VERSION 5.8 ;
BUSBITCHARS "[]" ;
DIVIDERCHAR "/" ;
UNITS
    DATABASE MICRONS 1000 ;
END UNITS

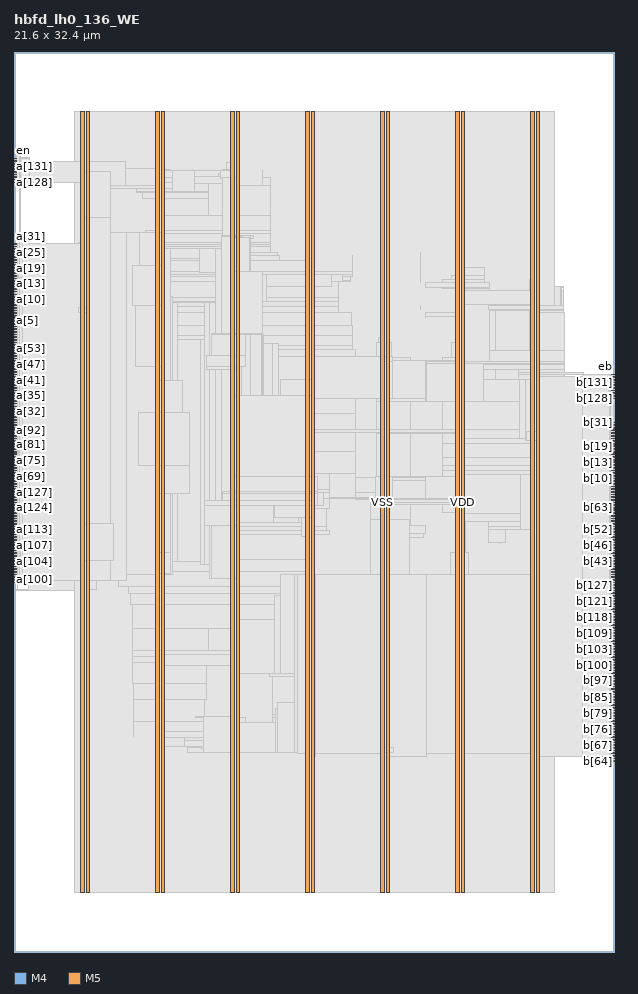
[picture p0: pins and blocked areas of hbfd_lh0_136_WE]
MACRO hbfd_lh0_136_WE
  FOREIGN hbfd_lh0_136_WE 0 0 ;
  CLASS BLOCK ;
  SIZE 21.6 BY 32.4 ;
  PIN a[0]
    DIRECTION INPUT ;
    USE SIGNAL ;
    PORT
      LAYER M4 ;
        RECT  0 22.512 0.084 22.536 ;
    END
  END a[0]
  PIN a[100]
    DIRECTION INPUT ;
    USE SIGNAL ;
    PORT
      LAYER M4 ;
        RECT  0 13.68 0.084 13.704 ;
    END
  END a[100]
  PIN a[101]
    DIRECTION INPUT ;
    USE SIGNAL ;
    PORT
      LAYER M4 ;
        RECT  0 13.776 0.084 13.8 ;
    END
  END a[101]
  PIN a[102]
    DIRECTION INPUT ;
    USE SIGNAL ;
    PORT
      LAYER M4 ;
        RECT  0 13.872 0.084 13.896 ;
    END
  END a[102]
  PIN a[103]
    DIRECTION INPUT ;
    USE SIGNAL ;
    PORT
      LAYER M4 ;
        RECT  0 13.968 0.084 13.992 ;
    END
  END a[103]
  PIN a[104]
    DIRECTION INPUT ;
    USE SIGNAL ;
    PORT
      LAYER M4 ;
        RECT  0 14.064 0.084 14.088 ;
    END
  END a[104]
  PIN a[105]
    DIRECTION INPUT ;
    USE SIGNAL ;
    PORT
      LAYER M4 ;
        RECT  0 14.16 0.084 14.184 ;
    END
  END a[105]
  PIN a[106]
    DIRECTION INPUT ;
    USE SIGNAL ;
    PORT
      LAYER M4 ;
        RECT  0 14.256 0.084 14.28 ;
    END
  END a[106]
  PIN a[107]
    DIRECTION INPUT ;
    USE SIGNAL ;
    PORT
      LAYER M4 ;
        RECT  0 14.352 0.084 14.376 ;
    END
  END a[107]
  PIN a[108]
    DIRECTION INPUT ;
    USE SIGNAL ;
    PORT
      LAYER M4 ;
        RECT  0 14.448 0.084 14.472 ;
    END
  END a[108]
  PIN a[109]
    DIRECTION INPUT ;
    USE SIGNAL ;
    PORT
      LAYER M4 ;
        RECT  0 14.544 0.084 14.568 ;
    END
  END a[109]
  PIN a[10]
    DIRECTION INPUT ;
    USE SIGNAL ;
    PORT
      LAYER M4 ;
        RECT  0 23.472 0.084 23.496 ;
    END
  END a[10]
  PIN a[110]
    DIRECTION INPUT ;
    USE SIGNAL ;
    PORT
      LAYER M4 ;
        RECT  0 14.64 0.084 14.664 ;
    END
  END a[110]
  PIN a[111]
    DIRECTION INPUT ;
    USE SIGNAL ;
    PORT
      LAYER M4 ;
        RECT  0 14.736 0.084 14.76 ;
    END
  END a[111]
  PIN a[112]
    DIRECTION INPUT ;
    USE SIGNAL ;
    PORT
      LAYER M4 ;
        RECT  0 14.832 0.084 14.856 ;
    END
  END a[112]
  PIN a[113]
    DIRECTION INPUT ;
    USE SIGNAL ;
    PORT
      LAYER M4 ;
        RECT  0 14.928 0.084 14.952 ;
    END
  END a[113]
  PIN a[114]
    DIRECTION INPUT ;
    USE SIGNAL ;
    PORT
      LAYER M4 ;
        RECT  0 15.024 0.084 15.048 ;
    END
  END a[114]
  PIN a[115]
    DIRECTION INPUT ;
    USE SIGNAL ;
    PORT
      LAYER M4 ;
        RECT  0 15.12 0.084 15.144 ;
    END
  END a[115]
  PIN a[116]
    DIRECTION INPUT ;
    USE SIGNAL ;
    PORT
      LAYER M4 ;
        RECT  0 15.216 0.084 15.24 ;
    END
  END a[116]
  PIN a[117]
    DIRECTION INPUT ;
    USE SIGNAL ;
    PORT
      LAYER M4 ;
        RECT  0 15.312 0.084 15.336 ;
    END
  END a[117]
  PIN a[118]
    DIRECTION INPUT ;
    USE SIGNAL ;
    PORT
      LAYER M4 ;
        RECT  0 15.408 0.084 15.432 ;
    END
  END a[118]
  PIN a[119]
    DIRECTION INPUT ;
    USE SIGNAL ;
    PORT
      LAYER M4 ;
        RECT  0 15.504 0.084 15.528 ;
    END
  END a[119]
  PIN a[11]
    DIRECTION INPUT ;
    USE SIGNAL ;
    PORT
      LAYER M4 ;
        RECT  0 23.568 0.084 23.592 ;
    END
  END a[11]
  PIN a[120]
    DIRECTION INPUT ;
    USE SIGNAL ;
    PORT
      LAYER M4 ;
        RECT  0 15.6 0.084 15.624 ;
    END
  END a[120]
  PIN a[121]
    DIRECTION INPUT ;
    USE SIGNAL ;
    PORT
      LAYER M4 ;
        RECT  0 15.696 0.084 15.72 ;
    END
  END a[121]
  PIN a[122]
    DIRECTION INPUT ;
    USE SIGNAL ;
    PORT
      LAYER M4 ;
        RECT  0 15.792 0.084 15.816 ;
    END
  END a[122]
  PIN a[123]
    DIRECTION INPUT ;
    USE SIGNAL ;
    PORT
      LAYER M4 ;
        RECT  0 15.888 0.084 15.912 ;
    END
  END a[123]
  PIN a[124]
    DIRECTION INPUT ;
    USE SIGNAL ;
    PORT
      LAYER M4 ;
        RECT  0 15.984 0.084 16.008 ;
    END
  END a[124]
  PIN a[125]
    DIRECTION INPUT ;
    USE SIGNAL ;
    PORT
      LAYER M4 ;
        RECT  0 16.08 0.084 16.104 ;
    END
  END a[125]
  PIN a[126]
    DIRECTION INPUT ;
    USE SIGNAL ;
    PORT
      LAYER M4 ;
        RECT  0 16.176 0.084 16.2 ;
    END
  END a[126]
  PIN a[127]
    DIRECTION INPUT ;
    USE SIGNAL ;
    PORT
      LAYER M4 ;
        RECT  0 16.272 0.084 16.296 ;
    END
  END a[127]
  PIN a[128]
    DIRECTION INPUT ;
    USE SIGNAL ;
    PORT
      LAYER M4 ;
        RECT  0 27.696 0.084 27.72 ;
    END
  END a[128]
  PIN a[129]
    DIRECTION INPUT ;
    USE SIGNAL ;
    PORT
      LAYER M4 ;
        RECT  0 27.792 0.084 27.816 ;
    END
  END a[129]
  PIN a[12]
    DIRECTION INPUT ;
    USE SIGNAL ;
    PORT
      LAYER M4 ;
        RECT  0 23.664 0.084 23.688 ;
    END
  END a[12]
  PIN a[130]
    DIRECTION INPUT ;
    USE SIGNAL ;
    PORT
      LAYER M4 ;
        RECT  0 27.888 0.084 27.912 ;
    END
  END a[130]
  PIN a[131]
    DIRECTION INPUT ;
    USE SIGNAL ;
    PORT
      LAYER M4 ;
        RECT  0 27.984 0.084 28.008 ;
    END
  END a[131]
  PIN a[132]
    DIRECTION INPUT ;
    USE SIGNAL ;
    PORT
      LAYER M4 ;
        RECT  0 28.08 0.084 28.104 ;
    END
  END a[132]
  PIN a[133]
    DIRECTION INPUT ;
    USE SIGNAL ;
    PORT
      LAYER M4 ;
        RECT  0 28.176 0.084 28.2 ;
    END
  END a[133]
  PIN a[134]
    DIRECTION INPUT ;
    USE SIGNAL ;
    PORT
      LAYER M4 ;
        RECT  0 28.272 0.084 28.296 ;
    END
  END a[134]
  PIN a[135]
    DIRECTION INPUT ;
    USE SIGNAL ;
    PORT
      LAYER M4 ;
        RECT  0 28.368 0.084 28.392 ;
    END
  END a[135]
  PIN a[13]
    DIRECTION INPUT ;
    USE SIGNAL ;
    PORT
      LAYER M4 ;
        RECT  0 23.76 0.084 23.784 ;
    END
  END a[13]
  PIN a[14]
    DIRECTION INPUT ;
    USE SIGNAL ;
    PORT
      LAYER M4 ;
        RECT  0 23.856 0.084 23.88 ;
    END
  END a[14]
  PIN a[15]
    DIRECTION INPUT ;
    USE SIGNAL ;
    PORT
      LAYER M4 ;
        RECT  0 23.952 0.084 23.976 ;
    END
  END a[15]
  PIN a[16]
    DIRECTION INPUT ;
    USE SIGNAL ;
    PORT
      LAYER M4 ;
        RECT  0 24.048 0.084 24.072 ;
    END
  END a[16]
  PIN a[17]
    DIRECTION INPUT ;
    USE SIGNAL ;
    PORT
      LAYER M4 ;
        RECT  0 24.144 0.084 24.168 ;
    END
  END a[17]
  PIN a[18]
    DIRECTION INPUT ;
    USE SIGNAL ;
    PORT
      LAYER M4 ;
        RECT  0 24.24 0.084 24.264 ;
    END
  END a[18]
  PIN a[19]
    DIRECTION INPUT ;
    USE SIGNAL ;
    PORT
      LAYER M4 ;
        RECT  0 24.336 0.084 24.36 ;
    END
  END a[19]
  PIN a[1]
    DIRECTION INPUT ;
    USE SIGNAL ;
    PORT
      LAYER M4 ;
        RECT  0 22.608 0.084 22.632 ;
    END
  END a[1]
  PIN a[20]
    DIRECTION INPUT ;
    USE SIGNAL ;
    PORT
      LAYER M4 ;
        RECT  0 24.432 0.084 24.456 ;
    END
  END a[20]
  PIN a[21]
    DIRECTION INPUT ;
    USE SIGNAL ;
    PORT
      LAYER M4 ;
        RECT  0 24.528 0.084 24.552 ;
    END
  END a[21]
  PIN a[22]
    DIRECTION INPUT ;
    USE SIGNAL ;
    PORT
      LAYER M4 ;
        RECT  0 24.624 0.084 24.648 ;
    END
  END a[22]
  PIN a[23]
    DIRECTION INPUT ;
    USE SIGNAL ;
    PORT
      LAYER M4 ;
        RECT  0 24.72 0.084 24.744 ;
    END
  END a[23]
  PIN a[24]
    DIRECTION INPUT ;
    USE SIGNAL ;
    PORT
      LAYER M4 ;
        RECT  0 24.816 0.084 24.84 ;
    END
  END a[24]
  PIN a[25]
    DIRECTION INPUT ;
    USE SIGNAL ;
    PORT
      LAYER M4 ;
        RECT  0 24.912 0.084 24.936 ;
    END
  END a[25]
  PIN a[26]
    DIRECTION INPUT ;
    USE SIGNAL ;
    PORT
      LAYER M4 ;
        RECT  0 25.008 0.084 25.032 ;
    END
  END a[26]
  PIN a[27]
    DIRECTION INPUT ;
    USE SIGNAL ;
    PORT
      LAYER M4 ;
        RECT  0 25.104 0.084 25.128 ;
    END
  END a[27]
  PIN a[28]
    DIRECTION INPUT ;
    USE SIGNAL ;
    PORT
      LAYER M4 ;
        RECT  0 25.2 0.084 25.224 ;
    END
  END a[28]
  PIN a[29]
    DIRECTION INPUT ;
    USE SIGNAL ;
    PORT
      LAYER M4 ;
        RECT  0 25.296 0.084 25.32 ;
    END
  END a[29]
  PIN a[2]
    DIRECTION INPUT ;
    USE SIGNAL ;
    PORT
      LAYER M4 ;
        RECT  0 22.704 0.084 22.728 ;
    END
  END a[2]
  PIN a[30]
    DIRECTION INPUT ;
    USE SIGNAL ;
    PORT
      LAYER M4 ;
        RECT  0 25.392 0.084 25.416 ;
    END
  END a[30]
  PIN a[31]
    DIRECTION INPUT ;
    USE SIGNAL ;
    PORT
      LAYER M4 ;
        RECT  0 25.488 0.084 25.512 ;
    END
  END a[31]
  PIN a[32]
    DIRECTION INPUT ;
    USE SIGNAL ;
    PORT
      LAYER M4 ;
        RECT  0 19.44 0.084 19.464 ;
    END
  END a[32]
  PIN a[33]
    DIRECTION INPUT ;
    USE SIGNAL ;
    PORT
      LAYER M4 ;
        RECT  0 19.536 0.084 19.56 ;
    END
  END a[33]
  PIN a[34]
    DIRECTION INPUT ;
    USE SIGNAL ;
    PORT
      LAYER M4 ;
        RECT  0 19.632 0.084 19.656 ;
    END
  END a[34]
  PIN a[35]
    DIRECTION INPUT ;
    USE SIGNAL ;
    PORT
      LAYER M4 ;
        RECT  0 19.728 0.084 19.752 ;
    END
  END a[35]
  PIN a[36]
    DIRECTION INPUT ;
    USE SIGNAL ;
    PORT
      LAYER M4 ;
        RECT  0 19.824 0.084 19.848 ;
    END
  END a[36]
  PIN a[37]
    DIRECTION INPUT ;
    USE SIGNAL ;
    PORT
      LAYER M4 ;
        RECT  0 19.92 0.084 19.944 ;
    END
  END a[37]
  PIN a[38]
    DIRECTION INPUT ;
    USE SIGNAL ;
    PORT
      LAYER M4 ;
        RECT  0 20.016 0.084 20.04 ;
    END
  END a[38]
  PIN a[39]
    DIRECTION INPUT ;
    USE SIGNAL ;
    PORT
      LAYER M4 ;
        RECT  0 20.112 0.084 20.136 ;
    END
  END a[39]
  PIN a[3]
    DIRECTION INPUT ;
    USE SIGNAL ;
    PORT
      LAYER M4 ;
        RECT  0 22.8 0.084 22.824 ;
    END
  END a[3]
  PIN a[40]
    DIRECTION INPUT ;
    USE SIGNAL ;
    PORT
      LAYER M4 ;
        RECT  0 20.208 0.084 20.232 ;
    END
  END a[40]
  PIN a[41]
    DIRECTION INPUT ;
    USE SIGNAL ;
    PORT
      LAYER M4 ;
        RECT  0 20.304 0.084 20.328 ;
    END
  END a[41]
  PIN a[42]
    DIRECTION INPUT ;
    USE SIGNAL ;
    PORT
      LAYER M4 ;
        RECT  0 20.4 0.084 20.424 ;
    END
  END a[42]
  PIN a[43]
    DIRECTION INPUT ;
    USE SIGNAL ;
    PORT
      LAYER M4 ;
        RECT  0 20.496 0.084 20.52 ;
    END
  END a[43]
  PIN a[44]
    DIRECTION INPUT ;
    USE SIGNAL ;
    PORT
      LAYER M4 ;
        RECT  0 20.592 0.084 20.616 ;
    END
  END a[44]
  PIN a[45]
    DIRECTION INPUT ;
    USE SIGNAL ;
    PORT
      LAYER M4 ;
        RECT  0 20.688 0.084 20.712 ;
    END
  END a[45]
  PIN a[46]
    DIRECTION INPUT ;
    USE SIGNAL ;
    PORT
      LAYER M4 ;
        RECT  0 20.784 0.084 20.808 ;
    END
  END a[46]
  PIN a[47]
    DIRECTION INPUT ;
    USE SIGNAL ;
    PORT
      LAYER M4 ;
        RECT  0 20.88 0.084 20.904 ;
    END
  END a[47]
  PIN a[48]
    DIRECTION INPUT ;
    USE SIGNAL ;
    PORT
      LAYER M4 ;
        RECT  0 20.976 0.084 21 ;
    END
  END a[48]
  PIN a[49]
    DIRECTION INPUT ;
    USE SIGNAL ;
    PORT
      LAYER M4 ;
        RECT  0 21.072 0.084 21.096 ;
    END
  END a[49]
  PIN a[4]
    DIRECTION INPUT ;
    USE SIGNAL ;
    PORT
      LAYER M4 ;
        RECT  0 22.896 0.084 22.92 ;
    END
  END a[4]
  PIN a[50]
    DIRECTION INPUT ;
    USE SIGNAL ;
    PORT
      LAYER M4 ;
        RECT  0 21.168 0.084 21.192 ;
    END
  END a[50]
  PIN a[51]
    DIRECTION INPUT ;
    USE SIGNAL ;
    PORT
      LAYER M4 ;
        RECT  0 21.264 0.084 21.288 ;
    END
  END a[51]
  PIN a[52]
    DIRECTION INPUT ;
    USE SIGNAL ;
    PORT
      LAYER M4 ;
        RECT  0 21.36 0.084 21.384 ;
    END
  END a[52]
  PIN a[53]
    DIRECTION INPUT ;
    USE SIGNAL ;
    PORT
      LAYER M4 ;
        RECT  0 21.456 0.084 21.48 ;
    END
  END a[53]
  PIN a[54]
    DIRECTION INPUT ;
    USE SIGNAL ;
    PORT
      LAYER M4 ;
        RECT  0 21.552 0.084 21.576 ;
    END
  END a[54]
  PIN a[55]
    DIRECTION INPUT ;
    USE SIGNAL ;
    PORT
      LAYER M4 ;
        RECT  0 21.648 0.084 21.672 ;
    END
  END a[55]
  PIN a[56]
    DIRECTION INPUT ;
    USE SIGNAL ;
    PORT
      LAYER M4 ;
        RECT  0 21.744 0.084 21.768 ;
    END
  END a[56]
  PIN a[57]
    DIRECTION INPUT ;
    USE SIGNAL ;
    PORT
      LAYER M4 ;
        RECT  0 21.84 0.084 21.864 ;
    END
  END a[57]
  PIN a[58]
    DIRECTION INPUT ;
    USE SIGNAL ;
    PORT
      LAYER M4 ;
        RECT  0 21.936 0.084 21.96 ;
    END
  END a[58]
  PIN a[59]
    DIRECTION INPUT ;
    USE SIGNAL ;
    PORT
      LAYER M4 ;
        RECT  0 22.032 0.084 22.056 ;
    END
  END a[59]
  PIN a[5]
    DIRECTION INPUT ;
    USE SIGNAL ;
    PORT
      LAYER M4 ;
        RECT  0 22.992 0.084 23.016 ;
    END
  END a[5]
  PIN a[60]
    DIRECTION INPUT ;
    USE SIGNAL ;
    PORT
      LAYER M4 ;
        RECT  0 22.128 0.084 22.152 ;
    END
  END a[60]
  PIN a[61]
    DIRECTION INPUT ;
    USE SIGNAL ;
    PORT
      LAYER M4 ;
        RECT  0 22.224 0.084 22.248 ;
    END
  END a[61]
  PIN a[62]
    DIRECTION INPUT ;
    USE SIGNAL ;
    PORT
      LAYER M4 ;
        RECT  0 22.32 0.084 22.344 ;
    END
  END a[62]
  PIN a[63]
    DIRECTION INPUT ;
    USE SIGNAL ;
    PORT
      LAYER M4 ;
        RECT  0 22.416 0.084 22.44 ;
    END
  END a[63]
  PIN a[64]
    DIRECTION INPUT ;
    USE SIGNAL ;
    PORT
      LAYER M4 ;
        RECT  0 16.368 0.084 16.392 ;
    END
  END a[64]
  PIN a[65]
    DIRECTION INPUT ;
    USE SIGNAL ;
    PORT
      LAYER M4 ;
        RECT  0 16.464 0.084 16.488 ;
    END
  END a[65]
  PIN a[66]
    DIRECTION INPUT ;
    USE SIGNAL ;
    PORT
      LAYER M4 ;
        RECT  0 16.56 0.084 16.584 ;
    END
  END a[66]
  PIN a[67]
    DIRECTION INPUT ;
    USE SIGNAL ;
    PORT
      LAYER M4 ;
        RECT  0 16.656 0.084 16.68 ;
    END
  END a[67]
  PIN a[68]
    DIRECTION INPUT ;
    USE SIGNAL ;
    PORT
      LAYER M4 ;
        RECT  0 16.752 0.084 16.776 ;
    END
  END a[68]
  PIN a[69]
    DIRECTION INPUT ;
    USE SIGNAL ;
    PORT
      LAYER M4 ;
        RECT  0 16.848 0.084 16.872 ;
    END
  END a[69]
  PIN a[6]
    DIRECTION INPUT ;
    USE SIGNAL ;
    PORT
      LAYER M4 ;
        RECT  0 23.088 0.084 23.112 ;
    END
  END a[6]
  PIN a[70]
    DIRECTION INPUT ;
    USE SIGNAL ;
    PORT
      LAYER M4 ;
        RECT  0 16.944 0.084 16.968 ;
    END
  END a[70]
  PIN a[71]
    DIRECTION INPUT ;
    USE SIGNAL ;
    PORT
      LAYER M4 ;
        RECT  0 17.04 0.084 17.064 ;
    END
  END a[71]
  PIN a[72]
    DIRECTION INPUT ;
    USE SIGNAL ;
    PORT
      LAYER M4 ;
        RECT  0 17.136 0.084 17.16 ;
    END
  END a[72]
  PIN a[73]
    DIRECTION INPUT ;
    USE SIGNAL ;
    PORT
      LAYER M4 ;
        RECT  0 17.232 0.084 17.256 ;
    END
  END a[73]
  PIN a[74]
    DIRECTION INPUT ;
    USE SIGNAL ;
    PORT
      LAYER M4 ;
        RECT  0 17.328 0.084 17.352 ;
    END
  END a[74]
  PIN a[75]
    DIRECTION INPUT ;
    USE SIGNAL ;
    PORT
      LAYER M4 ;
        RECT  0 17.424 0.084 17.448 ;
    END
  END a[75]
  PIN a[76]
    DIRECTION INPUT ;
    USE SIGNAL ;
    PORT
      LAYER M4 ;
        RECT  0 17.52 0.084 17.544 ;
    END
  END a[76]
  PIN a[77]
    DIRECTION INPUT ;
    USE SIGNAL ;
    PORT
      LAYER M4 ;
        RECT  0 17.616 0.084 17.64 ;
    END
  END a[77]
  PIN a[78]
    DIRECTION INPUT ;
    USE SIGNAL ;
    PORT
      LAYER M4 ;
        RECT  0 17.712 0.084 17.736 ;
    END
  END a[78]
  PIN a[79]
    DIRECTION INPUT ;
    USE SIGNAL ;
    PORT
      LAYER M4 ;
        RECT  0 17.808 0.084 17.832 ;
    END
  END a[79]
  PIN a[7]
    DIRECTION INPUT ;
    USE SIGNAL ;
    PORT
      LAYER M4 ;
        RECT  0 23.184 0.084 23.208 ;
    END
  END a[7]
  PIN a[80]
    DIRECTION INPUT ;
    USE SIGNAL ;
    PORT
      LAYER M4 ;
        RECT  0 17.904 0.084 17.928 ;
    END
  END a[80]
  PIN a[81]
    DIRECTION INPUT ;
    USE SIGNAL ;
    PORT
      LAYER M4 ;
        RECT  0 18 0.084 18.024 ;
    END
  END a[81]
  PIN a[82]
    DIRECTION INPUT ;
    USE SIGNAL ;
    PORT
      LAYER M4 ;
        RECT  0 18.096 0.084 18.12 ;
    END
  END a[82]
  PIN a[83]
    DIRECTION INPUT ;
    USE SIGNAL ;
    PORT
      LAYER M4 ;
        RECT  0 18.192 0.084 18.216 ;
    END
  END a[83]
  PIN a[84]
    DIRECTION INPUT ;
    USE SIGNAL ;
    PORT
      LAYER M4 ;
        RECT  0 18.288 0.084 18.312 ;
    END
  END a[84]
  PIN a[85]
    DIRECTION INPUT ;
    USE SIGNAL ;
    PORT
      LAYER M4 ;
        RECT  0 18.384 0.084 18.408 ;
    END
  END a[85]
  PIN a[86]
    DIRECTION INPUT ;
    USE SIGNAL ;
    PORT
      LAYER M4 ;
        RECT  0 18.48 0.084 18.504 ;
    END
  END a[86]
  PIN a[87]
    DIRECTION INPUT ;
    USE SIGNAL ;
    PORT
      LAYER M4 ;
        RECT  0 18.576 0.084 18.6 ;
    END
  END a[87]
  PIN a[88]
    DIRECTION INPUT ;
    USE SIGNAL ;
    PORT
      LAYER M4 ;
        RECT  0 18.672 0.084 18.696 ;
    END
  END a[88]
  PIN a[89]
    DIRECTION INPUT ;
    USE SIGNAL ;
    PORT
      LAYER M4 ;
        RECT  0 18.768 0.084 18.792 ;
    END
  END a[89]
  PIN a[8]
    DIRECTION INPUT ;
    USE SIGNAL ;
    PORT
      LAYER M4 ;
        RECT  0 23.28 0.084 23.304 ;
    END
  END a[8]
  PIN a[90]
    DIRECTION INPUT ;
    USE SIGNAL ;
    PORT
      LAYER M4 ;
        RECT  0 18.864 0.084 18.888 ;
    END
  END a[90]
  PIN a[91]
    DIRECTION INPUT ;
    USE SIGNAL ;
    PORT
      LAYER M4 ;
        RECT  0 18.96 0.084 18.984 ;
    END
  END a[91]
  PIN a[92]
    DIRECTION INPUT ;
    USE SIGNAL ;
    PORT
      LAYER M4 ;
        RECT  0 19.056 0.084 19.08 ;
    END
  END a[92]
  PIN a[93]
    DIRECTION INPUT ;
    USE SIGNAL ;
    PORT
      LAYER M4 ;
        RECT  0 19.152 0.084 19.176 ;
    END
  END a[93]
  PIN a[94]
    DIRECTION INPUT ;
    USE SIGNAL ;
    PORT
      LAYER M4 ;
        RECT  0 19.248 0.084 19.272 ;
    END
  END a[94]
  PIN a[95]
    DIRECTION INPUT ;
    USE SIGNAL ;
    PORT
      LAYER M4 ;
        RECT  0 19.344 0.084 19.368 ;
    END
  END a[95]
  PIN a[96]
    DIRECTION INPUT ;
    USE SIGNAL ;
    PORT
      LAYER M4 ;
        RECT  0 13.296 0.084 13.32 ;
    END
  END a[96]
  PIN a[97]
    DIRECTION INPUT ;
    USE SIGNAL ;
    PORT
      LAYER M4 ;
        RECT  0 13.392 0.084 13.416 ;
    END
  END a[97]
  PIN a[98]
    DIRECTION INPUT ;
    USE SIGNAL ;
    PORT
      LAYER M4 ;
        RECT  0 13.488 0.084 13.512 ;
    END
  END a[98]
  PIN a[99]
    DIRECTION INPUT ;
    USE SIGNAL ;
    PORT
      LAYER M4 ;
        RECT  0 13.584 0.084 13.608 ;
    END
  END a[99]
  PIN a[9]
    DIRECTION INPUT ;
    USE SIGNAL ;
    PORT
      LAYER M4 ;
        RECT  0 23.376 0.084 23.4 ;
    END
  END a[9]
  PIN b[0]
    DIRECTION OUTPUT ;
    USE SIGNAL ;
    PORT
      LAYER M4 ;
        RECT  21.516 16.08 21.6 16.104 ;
    END
  END b[0]
  PIN b[100]
    DIRECTION OUTPUT ;
    USE SIGNAL ;
    PORT
      LAYER M4 ;
        RECT  21.516 10.32 21.6 10.344 ;
    END
  END b[100]
  PIN b[101]
    DIRECTION OUTPUT ;
    USE SIGNAL ;
    PORT
      LAYER M4 ;
        RECT  21.516 10.416 21.6 10.44 ;
    END
  END b[101]
  PIN b[102]
    DIRECTION OUTPUT ;
    USE SIGNAL ;
    PORT
      LAYER M4 ;
        RECT  21.516 10.512 21.6 10.536 ;
    END
  END b[102]
  PIN b[103]
    DIRECTION OUTPUT ;
    USE SIGNAL ;
    PORT
      LAYER M4 ;
        RECT  21.516 10.608 21.6 10.632 ;
    END
  END b[103]
  PIN b[104]
    DIRECTION OUTPUT ;
    USE SIGNAL ;
    PORT
      LAYER M4 ;
        RECT  21.516 10.704 21.6 10.728 ;
    END
  END b[104]
  PIN b[105]
    DIRECTION OUTPUT ;
    USE SIGNAL ;
    PORT
      LAYER M4 ;
        RECT  21.516 10.8 21.6 10.824 ;
    END
  END b[105]
  PIN b[106]
    DIRECTION OUTPUT ;
    USE SIGNAL ;
    PORT
      LAYER M4 ;
        RECT  21.516 10.896 21.6 10.92 ;
    END
  END b[106]
  PIN b[107]
    DIRECTION OUTPUT ;
    USE SIGNAL ;
    PORT
      LAYER M4 ;
        RECT  21.516 10.992 21.6 11.016 ;
    END
  END b[107]
  PIN b[108]
    DIRECTION OUTPUT ;
    USE SIGNAL ;
    PORT
      LAYER M4 ;
        RECT  21.516 11.088 21.6 11.112 ;
    END
  END b[108]
  PIN b[109]
    DIRECTION OUTPUT ;
    USE SIGNAL ;
    PORT
      LAYER M4 ;
        RECT  21.516 11.184 21.6 11.208 ;
    END
  END b[109]
  PIN b[10]
    DIRECTION OUTPUT ;
    USE SIGNAL ;
    PORT
      LAYER M4 ;
        RECT  21.516 17.04 21.6 17.064 ;
    END
  END b[10]
  PIN b[110]
    DIRECTION OUTPUT ;
    USE SIGNAL ;
    PORT
      LAYER M4 ;
        RECT  21.516 11.28 21.6 11.304 ;
    END
  END b[110]
  PIN b[111]
    DIRECTION OUTPUT ;
    USE SIGNAL ;
    PORT
      LAYER M4 ;
        RECT  21.516 11.376 21.6 11.4 ;
    END
  END b[111]
  PIN b[112]
    DIRECTION OUTPUT ;
    USE SIGNAL ;
    PORT
      LAYER M4 ;
        RECT  21.516 11.472 21.6 11.496 ;
    END
  END b[112]
  PIN b[113]
    DIRECTION OUTPUT ;
    USE SIGNAL ;
    PORT
      LAYER M4 ;
        RECT  21.516 11.568 21.6 11.592 ;
    END
  END b[113]
  PIN b[114]
    DIRECTION OUTPUT ;
    USE SIGNAL ;
    PORT
      LAYER M4 ;
        RECT  21.516 11.664 21.6 11.688 ;
    END
  END b[114]
  PIN b[115]
    DIRECTION OUTPUT ;
    USE SIGNAL ;
    PORT
      LAYER M4 ;
        RECT  21.516 11.76 21.6 11.784 ;
    END
  END b[115]
  PIN b[116]
    DIRECTION OUTPUT ;
    USE SIGNAL ;
    PORT
      LAYER M4 ;
        RECT  21.516 11.856 21.6 11.88 ;
    END
  END b[116]
  PIN b[117]
    DIRECTION OUTPUT ;
    USE SIGNAL ;
    PORT
      LAYER M4 ;
        RECT  21.516 11.952 21.6 11.976 ;
    END
  END b[117]
  PIN b[118]
    DIRECTION OUTPUT ;
    USE SIGNAL ;
    PORT
      LAYER M4 ;
        RECT  21.516 12.048 21.6 12.072 ;
    END
  END b[118]
  PIN b[119]
    DIRECTION OUTPUT ;
    USE SIGNAL ;
    PORT
      LAYER M4 ;
        RECT  21.516 12.144 21.6 12.168 ;
    END
  END b[119]
  PIN b[11]
    DIRECTION OUTPUT ;
    USE SIGNAL ;
    PORT
      LAYER M4 ;
        RECT  21.516 17.136 21.6 17.16 ;
    END
  END b[11]
  PIN b[120]
    DIRECTION OUTPUT ;
    USE SIGNAL ;
    PORT
      LAYER M4 ;
        RECT  21.516 12.24 21.6 12.264 ;
    END
  END b[120]
  PIN b[121]
    DIRECTION OUTPUT ;
    USE SIGNAL ;
    PORT
      LAYER M4 ;
        RECT  21.516 12.336 21.6 12.36 ;
    END
  END b[121]
  PIN b[122]
    DIRECTION OUTPUT ;
    USE SIGNAL ;
    PORT
      LAYER M4 ;
        RECT  21.516 12.432 21.6 12.456 ;
    END
  END b[122]
  PIN b[123]
    DIRECTION OUTPUT ;
    USE SIGNAL ;
    PORT
      LAYER M4 ;
        RECT  21.516 12.528 21.6 12.552 ;
    END
  END b[123]
  PIN b[124]
    DIRECTION OUTPUT ;
    USE SIGNAL ;
    PORT
      LAYER M4 ;
        RECT  21.516 12.624 21.6 12.648 ;
    END
  END b[124]
  PIN b[125]
    DIRECTION OUTPUT ;
    USE SIGNAL ;
    PORT
      LAYER M4 ;
        RECT  21.516 12.72 21.6 12.744 ;
    END
  END b[125]
  PIN b[126]
    DIRECTION OUTPUT ;
    USE SIGNAL ;
    PORT
      LAYER M4 ;
        RECT  21.516 12.816 21.6 12.84 ;
    END
  END b[126]
  PIN b[127]
    DIRECTION OUTPUT ;
    USE SIGNAL ;
    PORT
      LAYER M4 ;
        RECT  21.516 12.912 21.6 12.936 ;
    END
  END b[127]
  PIN b[128]
    DIRECTION OUTPUT ;
    USE SIGNAL ;
    PORT
      LAYER M4 ;
        RECT  21.516 19.92 21.6 19.944 ;
    END
  END b[128]
  PIN b[129]
    DIRECTION OUTPUT ;
    USE SIGNAL ;
    PORT
      LAYER M4 ;
        RECT  21.516 20.016 21.6 20.04 ;
    END
  END b[129]
  PIN b[12]
    DIRECTION OUTPUT ;
    USE SIGNAL ;
    PORT
      LAYER M4 ;
        RECT  21.516 17.232 21.6 17.256 ;
    END
  END b[12]
  PIN b[130]
    DIRECTION OUTPUT ;
    USE SIGNAL ;
    PORT
      LAYER M4 ;
        RECT  21.516 20.112 21.6 20.136 ;
    END
  END b[130]
  PIN b[131]
    DIRECTION OUTPUT ;
    USE SIGNAL ;
    PORT
      LAYER M4 ;
        RECT  21.516 20.208 21.6 20.232 ;
    END
  END b[131]
  PIN b[132]
    DIRECTION OUTPUT ;
    USE SIGNAL ;
    PORT
      LAYER M4 ;
        RECT  21.516 20.304 21.6 20.328 ;
    END
  END b[132]
  PIN b[133]
    DIRECTION OUTPUT ;
    USE SIGNAL ;
    PORT
      LAYER M4 ;
        RECT  21.516 20.4 21.6 20.424 ;
    END
  END b[133]
  PIN b[134]
    DIRECTION OUTPUT ;
    USE SIGNAL ;
    PORT
      LAYER M4 ;
        RECT  21.516 20.496 21.6 20.52 ;
    END
  END b[134]
  PIN b[135]
    DIRECTION OUTPUT ;
    USE SIGNAL ;
    PORT
      LAYER M4 ;
        RECT  21.516 20.592 21.6 20.616 ;
    END
  END b[135]
  PIN b[13]
    DIRECTION OUTPUT ;
    USE SIGNAL ;
    PORT
      LAYER M4 ;
        RECT  21.516 17.328 21.6 17.352 ;
    END
  END b[13]
  PIN b[14]
    DIRECTION OUTPUT ;
    USE SIGNAL ;
    PORT
      LAYER M4 ;
        RECT  21.516 17.424 21.6 17.448 ;
    END
  END b[14]
  PIN b[15]
    DIRECTION OUTPUT ;
    USE SIGNAL ;
    PORT
      LAYER M4 ;
        RECT  21.516 17.52 21.6 17.544 ;
    END
  END b[15]
  PIN b[16]
    DIRECTION OUTPUT ;
    USE SIGNAL ;
    PORT
      LAYER M4 ;
        RECT  21.516 17.616 21.6 17.64 ;
    END
  END b[16]
  PIN b[17]
    DIRECTION OUTPUT ;
    USE SIGNAL ;
    PORT
      LAYER M4 ;
        RECT  21.516 17.712 21.6 17.736 ;
    END
  END b[17]
  PIN b[18]
    DIRECTION OUTPUT ;
    USE SIGNAL ;
    PORT
      LAYER M4 ;
        RECT  21.516 17.808 21.6 17.832 ;
    END
  END b[18]
  PIN b[19]
    DIRECTION OUTPUT ;
    USE SIGNAL ;
    PORT
      LAYER M4 ;
        RECT  21.516 17.904 21.6 17.928 ;
    END
  END b[19]
  PIN b[1]
    DIRECTION OUTPUT ;
    USE SIGNAL ;
    PORT
      LAYER M4 ;
        RECT  21.516 16.176 21.6 16.2 ;
    END
  END b[1]
  PIN b[20]
    DIRECTION OUTPUT ;
    USE SIGNAL ;
    PORT
      LAYER M4 ;
        RECT  21.516 18 21.6 18.024 ;
    END
  END b[20]
  PIN b[21]
    DIRECTION OUTPUT ;
    USE SIGNAL ;
    PORT
      LAYER M4 ;
        RECT  21.516 18.096 21.6 18.12 ;
    END
  END b[21]
  PIN b[22]
    DIRECTION OUTPUT ;
    USE SIGNAL ;
    PORT
      LAYER M4 ;
        RECT  21.516 18.192 21.6 18.216 ;
    END
  END b[22]
  PIN b[23]
    DIRECTION OUTPUT ;
    USE SIGNAL ;
    PORT
      LAYER M4 ;
        RECT  21.516 18.288 21.6 18.312 ;
    END
  END b[23]
  PIN b[24]
    DIRECTION OUTPUT ;
    USE SIGNAL ;
    PORT
      LAYER M4 ;
        RECT  21.516 18.384 21.6 18.408 ;
    END
  END b[24]
  PIN b[25]
    DIRECTION OUTPUT ;
    USE SIGNAL ;
    PORT
      LAYER M4 ;
        RECT  21.516 18.48 21.6 18.504 ;
    END
  END b[25]
  PIN b[26]
    DIRECTION OUTPUT ;
    USE SIGNAL ;
    PORT
      LAYER M4 ;
        RECT  21.516 18.576 21.6 18.6 ;
    END
  END b[26]
  PIN b[27]
    DIRECTION OUTPUT ;
    USE SIGNAL ;
    PORT
      LAYER M4 ;
        RECT  21.516 18.672 21.6 18.696 ;
    END
  END b[27]
  PIN b[28]
    DIRECTION OUTPUT ;
    USE SIGNAL ;
    PORT
      LAYER M4 ;
        RECT  21.516 18.768 21.6 18.792 ;
    END
  END b[28]
  PIN b[29]
    DIRECTION OUTPUT ;
    USE SIGNAL ;
    PORT
      LAYER M4 ;
        RECT  21.516 18.864 21.6 18.888 ;
    END
  END b[29]
  PIN b[2]
    DIRECTION OUTPUT ;
    USE SIGNAL ;
    PORT
      LAYER M4 ;
        RECT  21.516 16.272 21.6 16.296 ;
    END
  END b[2]
  PIN b[30]
    DIRECTION OUTPUT ;
    USE SIGNAL ;
    PORT
      LAYER M4 ;
        RECT  21.516 18.96 21.6 18.984 ;
    END
  END b[30]
  PIN b[31]
    DIRECTION OUTPUT ;
    USE SIGNAL ;
    PORT
      LAYER M4 ;
        RECT  21.516 19.056 21.6 19.08 ;
    END
  END b[31]
  PIN b[32]
    DIRECTION OUTPUT ;
    USE SIGNAL ;
    PORT
      LAYER M4 ;
        RECT  21.516 13.008 21.6 13.032 ;
    END
  END b[32]
  PIN b[33]
    DIRECTION OUTPUT ;
    USE SIGNAL ;
    PORT
      LAYER M4 ;
        RECT  21.516 13.104 21.6 13.128 ;
    END
  END b[33]
  PIN b[34]
    DIRECTION OUTPUT ;
    USE SIGNAL ;
    PORT
      LAYER M4 ;
        RECT  21.516 13.2 21.6 13.224 ;
    END
  END b[34]
  PIN b[35]
    DIRECTION OUTPUT ;
    USE SIGNAL ;
    PORT
      LAYER M4 ;
        RECT  21.516 13.296 21.6 13.32 ;
    END
  END b[35]
  PIN b[36]
    DIRECTION OUTPUT ;
    USE SIGNAL ;
    PORT
      LAYER M4 ;
        RECT  21.516 13.392 21.6 13.416 ;
    END
  END b[36]
  PIN b[37]
    DIRECTION OUTPUT ;
    USE SIGNAL ;
    PORT
      LAYER M4 ;
        RECT  21.516 13.488 21.6 13.512 ;
    END
  END b[37]
  PIN b[38]
    DIRECTION OUTPUT ;
    USE SIGNAL ;
    PORT
      LAYER M4 ;
        RECT  21.516 13.584 21.6 13.608 ;
    END
  END b[38]
  PIN b[39]
    DIRECTION OUTPUT ;
    USE SIGNAL ;
    PORT
      LAYER M4 ;
        RECT  21.516 13.68 21.6 13.704 ;
    END
  END b[39]
  PIN b[3]
    DIRECTION OUTPUT ;
    USE SIGNAL ;
    PORT
      LAYER M4 ;
        RECT  21.516 16.368 21.6 16.392 ;
    END
  END b[3]
  PIN b[40]
    DIRECTION OUTPUT ;
    USE SIGNAL ;
    PORT
      LAYER M4 ;
        RECT  21.516 13.776 21.6 13.8 ;
    END
  END b[40]
  PIN b[41]
    DIRECTION OUTPUT ;
    USE SIGNAL ;
    PORT
      LAYER M4 ;
        RECT  21.516 13.872 21.6 13.896 ;
    END
  END b[41]
  PIN b[42]
    DIRECTION OUTPUT ;
    USE SIGNAL ;
    PORT
      LAYER M4 ;
        RECT  21.516 13.968 21.6 13.992 ;
    END
  END b[42]
  PIN b[43]
    DIRECTION OUTPUT ;
    USE SIGNAL ;
    PORT
      LAYER M4 ;
        RECT  21.516 14.064 21.6 14.088 ;
    END
  END b[43]
  PIN b[44]
    DIRECTION OUTPUT ;
    USE SIGNAL ;
    PORT
      LAYER M4 ;
        RECT  21.516 14.16 21.6 14.184 ;
    END
  END b[44]
  PIN b[45]
    DIRECTION OUTPUT ;
    USE SIGNAL ;
    PORT
      LAYER M4 ;
        RECT  21.516 14.256 21.6 14.28 ;
    END
  END b[45]
  PIN b[46]
    DIRECTION OUTPUT ;
    USE SIGNAL ;
    PORT
      LAYER M4 ;
        RECT  21.516 14.352 21.6 14.376 ;
    END
  END b[46]
  PIN b[47]
    DIRECTION OUTPUT ;
    USE SIGNAL ;
    PORT
      LAYER M4 ;
        RECT  21.516 14.448 21.6 14.472 ;
    END
  END b[47]
  PIN b[48]
    DIRECTION OUTPUT ;
    USE SIGNAL ;
    PORT
      LAYER M4 ;
        RECT  21.516 14.544 21.6 14.568 ;
    END
  END b[48]
  PIN b[49]
    DIRECTION OUTPUT ;
    USE SIGNAL ;
    PORT
      LAYER M4 ;
        RECT  21.516 14.64 21.6 14.664 ;
    END
  END b[49]
  PIN b[4]
    DIRECTION OUTPUT ;
    USE SIGNAL ;
    PORT
      LAYER M4 ;
        RECT  21.516 16.464 21.6 16.488 ;
    END
  END b[4]
  PIN b[50]
    DIRECTION OUTPUT ;
    USE SIGNAL ;
    PORT
      LAYER M4 ;
        RECT  21.516 14.736 21.6 14.76 ;
    END
  END b[50]
  PIN b[51]
    DIRECTION OUTPUT ;
    USE SIGNAL ;
    PORT
      LAYER M4 ;
        RECT  21.516 14.832 21.6 14.856 ;
    END
  END b[51]
  PIN b[52]
    DIRECTION OUTPUT ;
    USE SIGNAL ;
    PORT
      LAYER M4 ;
        RECT  21.516 14.928 21.6 14.952 ;
    END
  END b[52]
  PIN b[53]
    DIRECTION OUTPUT ;
    USE SIGNAL ;
    PORT
      LAYER M4 ;
        RECT  21.516 15.024 21.6 15.048 ;
    END
  END b[53]
  PIN b[54]
    DIRECTION OUTPUT ;
    USE SIGNAL ;
    PORT
      LAYER M4 ;
        RECT  21.516 15.12 21.6 15.144 ;
    END
  END b[54]
  PIN b[55]
    DIRECTION OUTPUT ;
    USE SIGNAL ;
    PORT
      LAYER M4 ;
        RECT  21.516 15.216 21.6 15.24 ;
    END
  END b[55]
  PIN b[56]
    DIRECTION OUTPUT ;
    USE SIGNAL ;
    PORT
      LAYER M4 ;
        RECT  21.516 15.312 21.6 15.336 ;
    END
  END b[56]
  PIN b[57]
    DIRECTION OUTPUT ;
    USE SIGNAL ;
    PORT
      LAYER M4 ;
        RECT  21.516 15.408 21.6 15.432 ;
    END
  END b[57]
  PIN b[58]
    DIRECTION OUTPUT ;
    USE SIGNAL ;
    PORT
      LAYER M4 ;
        RECT  21.516 15.504 21.6 15.528 ;
    END
  END b[58]
  PIN b[59]
    DIRECTION OUTPUT ;
    USE SIGNAL ;
    PORT
      LAYER M4 ;
        RECT  21.516 15.6 21.6 15.624 ;
    END
  END b[59]
  PIN b[5]
    DIRECTION OUTPUT ;
    USE SIGNAL ;
    PORT
      LAYER M4 ;
        RECT  21.516 16.56 21.6 16.584 ;
    END
  END b[5]
  PIN b[60]
    DIRECTION OUTPUT ;
    USE SIGNAL ;
    PORT
      LAYER M4 ;
        RECT  21.516 15.696 21.6 15.72 ;
    END
  END b[60]
  PIN b[61]
    DIRECTION OUTPUT ;
    USE SIGNAL ;
    PORT
      LAYER M4 ;
        RECT  21.516 15.792 21.6 15.816 ;
    END
  END b[61]
  PIN b[62]
    DIRECTION OUTPUT ;
    USE SIGNAL ;
    PORT
      LAYER M4 ;
        RECT  21.516 15.888 21.6 15.912 ;
    END
  END b[62]
  PIN b[63]
    DIRECTION OUTPUT ;
    USE SIGNAL ;
    PORT
      LAYER M4 ;
        RECT  21.516 15.984 21.6 16.008 ;
    END
  END b[63]
  PIN b[64]
    DIRECTION OUTPUT ;
    USE SIGNAL ;
    PORT
      LAYER M4 ;
        RECT  21.516 6.864 21.6 6.888 ;
    END
  END b[64]
  PIN b[65]
    DIRECTION OUTPUT ;
    USE SIGNAL ;
    PORT
      LAYER M4 ;
        RECT  21.516 6.96 21.6 6.984 ;
    END
  END b[65]
  PIN b[66]
    DIRECTION OUTPUT ;
    USE SIGNAL ;
    PORT
      LAYER M4 ;
        RECT  21.516 7.056 21.6 7.08 ;
    END
  END b[66]
  PIN b[67]
    DIRECTION OUTPUT ;
    USE SIGNAL ;
    PORT
      LAYER M4 ;
        RECT  21.516 7.152 21.6 7.176 ;
    END
  END b[67]
  PIN b[68]
    DIRECTION OUTPUT ;
    USE SIGNAL ;
    PORT
      LAYER M4 ;
        RECT  21.516 7.248 21.6 7.272 ;
    END
  END b[68]
  PIN b[69]
    DIRECTION OUTPUT ;
    USE SIGNAL ;
    PORT
      LAYER M4 ;
        RECT  21.516 7.344 21.6 7.368 ;
    END
  END b[69]
  PIN b[6]
    DIRECTION OUTPUT ;
    USE SIGNAL ;
    PORT
      LAYER M4 ;
        RECT  21.516 16.656 21.6 16.68 ;
    END
  END b[6]
  PIN b[70]
    DIRECTION OUTPUT ;
    USE SIGNAL ;
    PORT
      LAYER M4 ;
        RECT  21.516 7.44 21.6 7.464 ;
    END
  END b[70]
  PIN b[71]
    DIRECTION OUTPUT ;
    USE SIGNAL ;
    PORT
      LAYER M4 ;
        RECT  21.516 7.536 21.6 7.56 ;
    END
  END b[71]
  PIN b[72]
    DIRECTION OUTPUT ;
    USE SIGNAL ;
    PORT
      LAYER M4 ;
        RECT  21.516 7.632 21.6 7.656 ;
    END
  END b[72]
  PIN b[73]
    DIRECTION OUTPUT ;
    USE SIGNAL ;
    PORT
      LAYER M4 ;
        RECT  21.516 7.728 21.6 7.752 ;
    END
  END b[73]
  PIN b[74]
    DIRECTION OUTPUT ;
    USE SIGNAL ;
    PORT
      LAYER M4 ;
        RECT  21.516 7.824 21.6 7.848 ;
    END
  END b[74]
  PIN b[75]
    DIRECTION OUTPUT ;
    USE SIGNAL ;
    PORT
      LAYER M4 ;
        RECT  21.516 7.92 21.6 7.944 ;
    END
  END b[75]
  PIN b[76]
    DIRECTION OUTPUT ;
    USE SIGNAL ;
    PORT
      LAYER M4 ;
        RECT  21.516 8.016 21.6 8.04 ;
    END
  END b[76]
  PIN b[77]
    DIRECTION OUTPUT ;
    USE SIGNAL ;
    PORT
      LAYER M4 ;
        RECT  21.516 8.112 21.6 8.136 ;
    END
  END b[77]
  PIN b[78]
    DIRECTION OUTPUT ;
    USE SIGNAL ;
    PORT
      LAYER M4 ;
        RECT  21.516 8.208 21.6 8.232 ;
    END
  END b[78]
  PIN b[79]
    DIRECTION OUTPUT ;
    USE SIGNAL ;
    PORT
      LAYER M4 ;
        RECT  21.516 8.304 21.6 8.328 ;
    END
  END b[79]
  PIN b[7]
    DIRECTION OUTPUT ;
    USE SIGNAL ;
    PORT
      LAYER M4 ;
        RECT  21.516 16.752 21.6 16.776 ;
    END
  END b[7]
  PIN b[80]
    DIRECTION OUTPUT ;
    USE SIGNAL ;
    PORT
      LAYER M4 ;
        RECT  21.516 8.4 21.6 8.424 ;
    END
  END b[80]
  PIN b[81]
    DIRECTION OUTPUT ;
    USE SIGNAL ;
    PORT
      LAYER M4 ;
        RECT  21.516 8.496 21.6 8.52 ;
    END
  END b[81]
  PIN b[82]
    DIRECTION OUTPUT ;
    USE SIGNAL ;
    PORT
      LAYER M4 ;
        RECT  21.516 8.592 21.6 8.616 ;
    END
  END b[82]
  PIN b[83]
    DIRECTION OUTPUT ;
    USE SIGNAL ;
    PORT
      LAYER M4 ;
        RECT  21.516 8.688 21.6 8.712 ;
    END
  END b[83]
  PIN b[84]
    DIRECTION OUTPUT ;
    USE SIGNAL ;
    PORT
      LAYER M4 ;
        RECT  21.516 8.784 21.6 8.808 ;
    END
  END b[84]
  PIN b[85]
    DIRECTION OUTPUT ;
    USE SIGNAL ;
    PORT
      LAYER M4 ;
        RECT  21.516 8.88 21.6 8.904 ;
    END
  END b[85]
  PIN b[86]
    DIRECTION OUTPUT ;
    USE SIGNAL ;
    PORT
      LAYER M4 ;
        RECT  21.516 8.976 21.6 9 ;
    END
  END b[86]
  PIN b[87]
    DIRECTION OUTPUT ;
    USE SIGNAL ;
    PORT
      LAYER M4 ;
        RECT  21.516 9.072 21.6 9.096 ;
    END
  END b[87]
  PIN b[88]
    DIRECTION OUTPUT ;
    USE SIGNAL ;
    PORT
      LAYER M4 ;
        RECT  21.516 9.168 21.6 9.192 ;
    END
  END b[88]
  PIN b[89]
    DIRECTION OUTPUT ;
    USE SIGNAL ;
    PORT
      LAYER M4 ;
        RECT  21.516 9.264 21.6 9.288 ;
    END
  END b[89]
  PIN b[8]
    DIRECTION OUTPUT ;
    USE SIGNAL ;
    PORT
      LAYER M4 ;
        RECT  21.516 16.848 21.6 16.872 ;
    END
  END b[8]
  PIN b[90]
    DIRECTION OUTPUT ;
    USE SIGNAL ;
    PORT
      LAYER M4 ;
        RECT  21.516 9.36 21.6 9.384 ;
    END
  END b[90]
  PIN b[91]
    DIRECTION OUTPUT ;
    USE SIGNAL ;
    PORT
      LAYER M4 ;
        RECT  21.516 9.456 21.6 9.48 ;
    END
  END b[91]
  PIN b[92]
    DIRECTION OUTPUT ;
    USE SIGNAL ;
    PORT
      LAYER M4 ;
        RECT  21.516 9.552 21.6 9.576 ;
    END
  END b[92]
  PIN b[93]
    DIRECTION OUTPUT ;
    USE SIGNAL ;
    PORT
      LAYER M4 ;
        RECT  21.516 9.648 21.6 9.672 ;
    END
  END b[93]
  PIN b[94]
    DIRECTION OUTPUT ;
    USE SIGNAL ;
    PORT
      LAYER M4 ;
        RECT  21.516 9.744 21.6 9.768 ;
    END
  END b[94]
  PIN b[95]
    DIRECTION OUTPUT ;
    USE SIGNAL ;
    PORT
      LAYER M4 ;
        RECT  21.516 9.84 21.6 9.864 ;
    END
  END b[95]
  PIN b[96]
    DIRECTION OUTPUT ;
    USE SIGNAL ;
    PORT
      LAYER M4 ;
        RECT  21.516 9.936 21.6 9.96 ;
    END
  END b[96]
  PIN b[97]
    DIRECTION OUTPUT ;
    USE SIGNAL ;
    PORT
      LAYER M4 ;
        RECT  21.516 10.032 21.6 10.056 ;
    END
  END b[97]
  PIN b[98]
    DIRECTION OUTPUT ;
    USE SIGNAL ;
    PORT
      LAYER M4 ;
        RECT  21.516 10.128 21.6 10.152 ;
    END
  END b[98]
  PIN b[99]
    DIRECTION OUTPUT ;
    USE SIGNAL ;
    PORT
      LAYER M4 ;
        RECT  21.516 10.224 21.6 10.248 ;
    END
  END b[99]
  PIN b[9]
    DIRECTION OUTPUT ;
    USE SIGNAL ;
    PORT
      LAYER M4 ;
        RECT  21.516 16.944 21.6 16.968 ;
    END
  END b[9]
  PIN ck
    DIRECTION INPUT ;
    USE SIGNAL ;
    PORT
      LAYER M4 ;
        RECT  0 28.464 0.084 28.488 ;
    END
  END ck
  PIN ck_o
    DIRECTION OUTPUT ;
    USE SIGNAL ;
    PORT
      LAYER M4 ;
        RECT  21.516 20.688 21.6 20.712 ;
    END
  END ck_o
  PIN eb
    DIRECTION OUTPUT ;
    USE SIGNAL ;
    PORT
      LAYER M4 ;
        RECT  21.516 20.784 21.6 20.808 ;
    END
  END eb
  PIN en
    DIRECTION INPUT ;
    USE SIGNAL ;
    PORT
      LAYER M4 ;
        RECT  0 28.56 0.084 28.584 ;
    END
  END en
  PIN VDD
    DIRECTION INOUT ;
    USE POWER ;
    PORT
      LAYER M5 ;
        RECT  18.792 2.151 18.912 30.249 ;
        RECT  16.092 2.151 16.212 30.249 ;
        RECT  13.392 2.151 13.512 30.249 ;
        RECT  10.692 2.151 10.812 30.249 ;
        RECT  7.992 2.151 8.112 30.249 ;
        RECT  5.292 2.151 5.412 30.249 ;
        RECT  2.592 2.151 2.712 30.249 ;
    END
  END VDD
  PIN VSS
    DIRECTION INOUT ;
    USE GROUND ;
    PORT
      LAYER M5 ;
        RECT  18.6 2.137 18.72 30.263 ;
        RECT  15.9 2.137 16.02 30.263 ;
        RECT  13.2 2.137 13.32 30.263 ;
        RECT  10.5 2.137 10.62 30.263 ;
        RECT  7.8 2.137 7.92 30.263 ;
        RECT  5.1 2.137 5.22 30.263 ;
        RECT  2.4 2.137 2.52 30.263 ;
    END
  END VSS
  OBS
    LAYER RVTN ;
     RECT  2.16 2.16 19.44 2.295 ;
     RECT  2.16 2.565 19.44 2.835 ;
     RECT  2.16 3.105 19.44 3.375 ;
     RECT  2.16 3.645 19.44 3.915 ;
     RECT  2.16 4.185 19.44 4.455 ;
     RECT  2.16 4.725 19.44 4.995 ;
     RECT  2.16 5.265 19.44 5.535 ;
     RECT  2.16 5.805 19.44 6.075 ;
     RECT  2.16 6.345 19.44 6.615 ;
     RECT  2.16 6.885 19.44 7.155 ;
     RECT  2.16 7.425 19.44 7.695 ;
     RECT  2.16 7.965 19.44 8.235 ;
     RECT  2.16 8.505 19.44 8.775 ;
     RECT  2.16 9.045 19.44 9.315 ;
     RECT  2.16 9.585 19.44 9.855 ;
     RECT  2.16 10.125 19.44 10.395 ;
     RECT  2.16 10.665 19.44 10.935 ;
     RECT  2.16 11.205 19.44 11.475 ;
     RECT  2.16 11.745 19.44 12.015 ;
     RECT  2.16 12.285 19.44 12.555 ;
     RECT  2.16 12.825 19.44 13.095 ;
     RECT  2.16 13.365 19.44 13.635 ;
     RECT  2.16 13.905 19.44 14.175 ;
     RECT  2.16 14.445 19.44 14.715 ;
     RECT  2.16 14.985 19.44 15.255 ;
     RECT  2.16 15.525 19.44 15.795 ;
     RECT  2.16 16.065 19.44 16.335 ;
     RECT  2.16 16.605 19.44 16.875 ;
     RECT  2.16 17.145 19.44 17.415 ;
     RECT  2.16 17.685 19.44 17.955 ;
     RECT  2.16 18.225 19.44 18.495 ;
     RECT  2.16 18.765 19.44 19.035 ;
     RECT  2.16 19.305 19.44 19.575 ;
     RECT  2.16 19.845 19.44 20.115 ;
     RECT  2.16 20.385 19.44 20.655 ;
     RECT  2.16 20.925 19.44 21.195 ;
     RECT  2.16 21.465 19.44 21.735 ;
     RECT  2.16 22.005 19.44 22.275 ;
     RECT  2.16 22.545 19.44 22.815 ;
     RECT  2.16 23.085 19.44 23.355 ;
     RECT  2.16 23.625 19.44 23.895 ;
     RECT  2.16 24.165 19.44 24.435 ;
     RECT  2.16 24.705 19.44 24.975 ;
     RECT  2.16 25.245 19.44 25.515 ;
     RECT  2.16 25.785 19.44 26.055 ;
     RECT  2.16 26.325 19.44 26.595 ;
     RECT  2.16 26.865 19.44 27.135 ;
     RECT  2.16 27.405 19.44 27.675 ;
     RECT  2.16 27.945 19.44 28.215 ;
     RECT  2.16 28.485 19.44 28.755 ;
     RECT  2.16 29.025 19.44 29.295 ;
     RECT  2.16 29.565 19.44 29.835 ;
     RECT  2.16 30.105 19.44 30.24 ;
    LAYER RVTP ;
     RECT  2.16 2.295 19.44 2.565 ;
     RECT  2.16 2.835 19.44 3.105 ;
     RECT  2.16 3.375 19.44 3.645 ;
     RECT  2.16 3.915 19.44 4.185 ;
     RECT  2.16 4.455 19.44 4.725 ;
     RECT  2.16 4.995 19.44 5.265 ;
     RECT  2.16 5.535 19.44 5.805 ;
     RECT  2.16 6.075 19.44 6.345 ;
     RECT  2.16 6.615 19.44 6.885 ;
     RECT  2.16 7.155 19.44 7.425 ;
     RECT  2.16 7.695 19.44 7.965 ;
     RECT  2.16 8.235 19.44 8.505 ;
     RECT  2.16 8.775 19.44 9.045 ;
     RECT  2.16 9.315 19.44 9.585 ;
     RECT  2.16 9.855 19.44 10.125 ;
     RECT  2.16 10.395 19.44 10.665 ;
     RECT  2.16 10.935 19.44 11.205 ;
     RECT  2.16 11.475 19.44 11.745 ;
     RECT  2.16 12.015 19.44 12.285 ;
     RECT  2.16 12.555 19.44 12.825 ;
     RECT  2.16 13.095 19.44 13.365 ;
     RECT  2.16 13.635 19.44 13.905 ;
     RECT  2.16 14.175 19.44 14.445 ;
     RECT  2.16 14.715 19.44 14.985 ;
     RECT  2.16 15.255 19.44 15.525 ;
     RECT  2.16 15.795 19.44 16.065 ;
     RECT  2.16 16.335 19.44 16.605 ;
     RECT  2.16 16.875 19.44 17.145 ;
     RECT  2.16 17.415 19.44 17.685 ;
     RECT  2.16 17.955 19.44 18.225 ;
     RECT  2.16 18.495 19.44 18.765 ;
     RECT  2.16 19.035 19.44 19.305 ;
     RECT  2.16 19.575 19.44 19.845 ;
     RECT  2.16 20.115 19.44 20.385 ;
     RECT  2.16 20.655 19.44 20.925 ;
     RECT  2.16 21.195 19.44 21.465 ;
     RECT  2.16 21.735 19.44 22.005 ;
     RECT  2.16 22.275 19.44 22.545 ;
     RECT  2.16 22.815 19.44 23.085 ;
     RECT  2.16 23.355 19.44 23.625 ;
     RECT  2.16 23.895 19.44 24.165 ;
     RECT  2.16 24.435 19.44 24.705 ;
     RECT  2.16 24.975 19.44 25.245 ;
     RECT  2.16 25.515 19.44 25.785 ;
     RECT  2.16 26.055 19.44 26.325 ;
     RECT  2.16 26.595 19.44 26.865 ;
     RECT  2.16 27.135 19.44 27.405 ;
     RECT  2.16 27.675 19.44 27.945 ;
     RECT  2.16 28.215 19.44 28.485 ;
     RECT  2.16 28.755 19.44 29.025 ;
     RECT  2.16 29.295 19.44 29.565 ;
     RECT  2.16 29.835 19.44 30.105 ;
    LAYER M1 ;
     RECT  2.16 2.151 19.44 30.249 ;
    LAYER M2 ;
     RECT  0.103 16.002 0.203 16.02 ;
     RECT  0.103 22.518 0.203 22.536 ;
     RECT  0.103 25.02 0.203 25.308 ;
     RECT  0.211 28.386 0.311 28.404 ;
     RECT  0.103 13.032 0.535 13.05 ;
     RECT  0.103 14.454 0.535 14.472 ;
     RECT  0.103 17.082 0.535 17.1 ;
     RECT  0.103 21.546 0.535 21.564 ;
     RECT  0.535 13.032 2.16 14.976 ;
     RECT  0.535 15.84 2.16 15.858 ;
     RECT  0.535 17.082 2.16 18.216 ;
     RECT  0.535 21.546 2.16 22.23 ;
     RECT  0.203 25.29 2.16 25.308 ;
     RECT  0.535 27.918 2.16 27.936 ;
     RECT  2.16 2.151 19.44 30.249 ;
     RECT  19.44 10.026 19.679 18.684 ;
     RECT  19.44 22.86 19.679 23.958 ;
     RECT  19.679 22.986 19.715 23.958 ;
     RECT  19.715 22.986 19.751 23.184 ;
     RECT  19.715 23.94 19.787 23.958 ;
     RECT  19.751 22.986 19.823 23.004 ;
     RECT  19.44 7.056 19.895 9.234 ;
     RECT  19.895 7.056 19.931 9.144 ;
     RECT  19.679 17.19 20.471 18.684 ;
     RECT  19.679 10.026 20.507 16.398 ;
     RECT  20.471 17.19 20.507 17.208 ;
     RECT  19.44 20.826 20.507 20.844 ;
     RECT  20.507 10.026 21.415 13.626 ;
     RECT  19.931 7.056 21.479 8.46 ;
     RECT  21.415 9.486 21.479 13.626 ;
     RECT  20.507 14.724 21.479 16.398 ;
     RECT  20.471 18.036 21.479 18.684 ;
     RECT  21.199 20.322 21.479 20.34 ;
     RECT  21.479 7.056 21.515 7.074 ;
     RECT  21.479 7.866 21.515 8.334 ;
     RECT  21.479 9.486 21.515 13.428 ;
     RECT  21.479 14.724 21.515 14.742 ;
     RECT  21.479 15.732 21.515 16.398 ;
     RECT  21.479 18.036 21.515 18.594 ;
     RECT  21.515 9.558 21.587 9.576 ;
     RECT  21.515 12.681 21.587 12.699 ;
    LAYER M3 ;
     RECT  2.415 2.143 2.505 2.413 ;
     RECT  5.115 2.143 5.205 2.413 ;
     RECT  7.815 2.143 7.905 2.413 ;
     RECT  10.515 2.143 10.605 2.413 ;
     RECT  13.215 2.143 13.305 2.413 ;
     RECT  15.915 2.143 16.005 2.413 ;
     RECT  18.615 2.143 18.705 2.413 ;
     RECT  21.492 6.859 21.51 6.955 ;
     RECT  10.515 2.413 10.797 7.051 ;
     RECT  10.515 7.051 10.854 7.147 ;
     RECT  13.215 2.413 13.497 7.147 ;
     RECT  10.224 7.147 10.854 7.181 ;
     RECT  21.456 6.955 21.51 7.243 ;
     RECT  6.228 7.195 6.858 7.357 ;
     RECT  7.815 2.413 8.097 7.357 ;
     RECT  13.215 7.147 13.554 7.373 ;
     RECT  6.228 7.357 8.097 7.387 ;
     RECT  10.224 7.181 10.797 7.435 ;
     RECT  21.42 7.243 21.51 7.531 ;
     RECT  6.12 7.387 8.097 7.619 ;
     RECT  9.288 7.339 9.306 7.627 ;
     RECT  10.188 7.435 10.797 7.627 ;
     RECT  21.276 7.531 21.51 7.661 ;
     RECT  7.815 7.619 8.097 7.723 ;
     RECT  5.115 2.413 5.397 7.735 ;
     RECT  6.12 7.619 6.858 7.735 ;
     RECT  5.115 7.735 6.858 7.933 ;
     RECT  13.215 7.373 13.497 8.251 ;
     RECT  14.832 7.051 14.85 8.251 ;
     RECT  4.284 7.771 4.302 8.311 ;
     RECT  5.076 7.933 6.858 8.311 ;
     RECT  21.312 7.661 21.51 8.339 ;
     RECT  7.815 7.723 8.334 8.429 ;
     RECT  21.312 8.339 21.474 8.429 ;
     RECT  9.288 7.627 10.797 8.437 ;
     RECT  21.42 8.429 21.474 8.465 ;
     RECT  13.215 8.251 13.698 8.477 ;
     RECT  14.832 8.251 14.922 8.477 ;
     RECT  9.288 8.437 10.818 8.537 ;
     RECT  13.215 8.477 13.497 8.779 ;
     RECT  19.656 8.491 19.674 8.779 ;
     RECT  4.284 8.311 6.858 9.085 ;
     RECT  19.656 8.779 19.926 9.149 ;
     RECT  19.656 9.149 19.89 9.239 ;
     RECT  18.615 2.413 18.897 9.259 ;
     RECT  19.656 9.239 19.674 9.259 ;
     RECT  12.816 8.779 13.497 9.355 ;
     RECT  21.42 8.465 21.438 9.451 ;
     RECT  15.915 2.413 16.197 9.547 ;
     RECT  21.42 9.451 21.51 9.553 ;
     RECT  4.284 9.085 6.93 9.661 ;
     RECT  12.816 9.355 13.698 9.787 ;
     RECT  14.832 8.477 14.85 9.787 ;
     RECT  9.288 8.537 10.797 9.931 ;
     RECT  12.816 9.787 14.85 9.959 ;
     RECT  7.815 8.429 8.097 10.027 ;
     RECT  14.22 9.959 14.85 10.027 ;
     RECT  21.42 9.553 21.582 10.027 ;
     RECT  9.18 9.931 10.797 10.123 ;
     RECT  14.22 10.027 14.958 10.157 ;
     RECT  21.276 10.027 21.582 10.157 ;
     RECT  18.615 9.259 19.674 10.171 ;
     RECT  21.348 10.157 21.582 10.229 ;
     RECT  4.248 9.661 6.93 10.435 ;
     RECT  7.815 10.027 8.19 10.435 ;
     RECT  9.036 10.123 10.797 10.435 ;
     RECT  7.815 10.435 10.797 10.471 ;
     RECT  18.216 10.171 19.674 10.499 ;
     RECT  4.248 10.435 7.002 10.651 ;
     RECT  7.815 10.471 10.854 10.651 ;
     RECT  21.42 10.229 21.582 10.829 ;
     RECT  4.248 10.651 10.854 10.859 ;
     RECT  20.484 10.891 20.502 10.975 ;
     RECT  20.484 10.975 20.574 10.987 ;
     RECT  14.22 10.157 14.238 11.179 ;
     RECT  20.448 10.987 20.574 11.213 ;
     RECT  7.815 10.859 10.854 11.237 ;
     RECT  14.22 11.179 14.85 11.309 ;
     RECT  20.448 11.213 20.538 11.399 ;
     RECT  4.248 10.859 7.002 11.641 ;
     RECT  7.815 11.237 10.797 11.641 ;
     RECT  18.615 10.499 19.674 11.755 ;
     RECT  18.216 11.755 19.674 12.389 ;
     RECT  21.492 10.829 21.582 12.427 ;
     RECT  21.348 12.427 21.582 12.451 ;
     RECT  12.816 9.959 13.497 12.475 ;
     RECT  4.248 11.641 10.797 12.523 ;
     RECT  20.484 11.399 20.538 12.676 ;
     RECT  21.276 12.451 21.582 12.676 ;
     RECT  20.484 12.676 21.582 12.704 ;
     RECT  18.615 12.389 19.674 12.715 ;
     RECT  20.484 12.704 21.51 12.715 ;
     RECT  18.615 12.715 21.51 12.785 ;
     RECT  17.64 12.559 17.73 12.859 ;
     RECT  12.528 12.475 13.497 12.865 ;
     RECT  14.22 11.309 14.238 12.865 ;
     RECT  12.528 12.865 14.238 12.893 ;
     RECT  17.568 12.859 17.73 12.893 ;
     RECT  17.568 12.893 17.586 12.899 ;
     RECT  4.176 12.523 10.797 12.901 ;
     RECT  2.415 2.413 2.697 13.063 ;
     RECT  4.104 12.901 10.797 13.171 ;
     RECT  15.915 9.547 16.254 13.297 ;
     RECT  0.108 13.027 0.126 13.325 ;
     RECT  21.42 12.785 21.51 13.469 ;
     RECT  2.415 13.063 2.97 13.483 ;
     RECT  12.816 12.893 14.238 13.559 ;
     RECT  15.696 13.297 16.254 13.567 ;
     RECT  21.456 13.469 21.51 13.631 ;
     RECT  2.304 13.483 2.97 13.711 ;
     RECT  3.744 13.171 10.797 13.711 ;
     RECT  2.304 13.711 10.797 14.135 ;
     RECT  0.54 13.567 0.558 14.203 ;
     RECT  15.696 13.567 16.362 14.369 ;
     RECT  21.492 13.631 21.51 14.443 ;
     RECT  0.18 14.203 0.558 14.449 ;
     RECT  2.304 14.135 6.102 14.573 ;
     RECT  18.615 12.785 20.682 14.573 ;
     RECT  21.456 14.443 21.51 14.635 ;
     RECT  0.108 14.449 0.558 14.669 ;
     RECT  17.496 14.719 17.514 14.755 ;
     RECT  14.22 13.559 14.238 14.917 ;
     RECT  21.42 14.635 21.51 14.923 ;
     RECT  6.84 14.135 10.797 15.025 ;
     RECT  14.22 14.917 14.742 15.061 ;
     RECT  0.144 14.669 0.558 15.149 ;
     RECT  2.34 14.573 6.102 15.179 ;
     RECT  6.84 15.025 11.358 15.179 ;
     RECT  17.064 14.755 17.694 15.211 ;
     RECT  18.615 14.573 20.466 15.211 ;
     RECT  17.064 15.211 20.466 15.307 ;
     RECT  4.104 15.179 6.102 15.331 ;
     RECT  6.84 15.179 11.25 15.331 ;
     RECT  14.22 15.061 14.814 15.359 ;
     RECT  2.34 15.179 3.366 15.457 ;
     RECT  15.915 14.369 16.254 15.493 ;
     RECT  17.064 15.307 20.502 15.493 ;
     RECT  21.348 14.923 21.51 15.521 ;
     RECT  21.384 15.521 21.51 15.557 ;
     RECT  12.816 13.559 13.497 15.565 ;
     RECT  14.22 15.359 14.274 15.565 ;
     RECT  2.268 15.457 3.366 15.725 ;
     RECT  15.915 15.493 20.502 15.835 ;
     RECT  0.18 15.149 0.558 15.883 ;
     RECT  4.104 15.331 11.25 15.961 ;
     RECT  0.108 15.883 0.558 16.013 ;
     RECT  0.108 16.013 0.198 16.028 ;
     RECT  12.816 15.565 14.274 16.105 ;
     RECT  15.408 15.835 20.502 16.105 ;
     RECT  12.816 16.105 20.502 16.169 ;
     RECT  20.448 16.169 20.502 16.259 ;
     RECT  12.816 16.169 19.674 16.303 ;
     RECT  21.42 15.557 21.51 16.315 ;
     RECT  21.348 16.315 21.51 16.403 ;
     RECT  21.348 16.403 21.438 16.493 ;
     RECT  12.276 16.303 19.674 16.529 ;
     RECT  2.304 15.725 3.366 16.645 ;
     RECT  4.104 15.961 11.358 16.645 ;
     RECT  20.448 16.259 20.466 17.035 ;
     RECT  0.144 16.028 0.162 17.068 ;
     RECT  12.276 16.529 19.098 17.069 ;
     RECT  13.032 17.069 19.098 17.117 ;
     RECT  20.448 17.035 20.502 17.131 ;
     RECT  0.108 17.068 0.162 17.165 ;
     RECT  19.908 17.131 20.502 17.213 ;
     RECT  21.42 16.493 21.438 17.213 ;
     RECT  2.304 16.645 11.358 17.221 ;
     RECT  12.276 17.069 12.294 17.221 ;
     RECT  15.408 17.117 19.098 17.323 ;
     RECT  19.908 17.213 20.466 17.323 ;
     RECT  0.18 17.179 0.198 17.357 ;
     RECT  15.408 17.323 20.466 17.519 ;
     RECT  15.408 17.519 19.926 17.789 ;
     RECT  2.304 17.221 12.294 18.029 ;
     RECT  0.54 17.617 0.558 18.091 ;
     RECT  0.324 18.091 0.558 18.221 ;
     RECT  15.408 17.789 19.89 18.293 ;
     RECT  0.54 18.221 0.558 18.317 ;
     RECT  21.456 17.515 21.51 18.427 ;
     RECT  21.42 18.427 21.51 18.599 ;
     RECT  21.42 18.599 21.474 18.605 ;
     RECT  13.032 17.117 14.274 18.661 ;
     RECT  15.408 18.293 19.818 18.661 ;
     RECT  21.456 18.605 21.474 18.689 ;
     RECT  2.304 18.029 6.894 18.797 ;
     RECT  13.032 18.661 19.818 18.797 ;
     RECT  3.708 18.797 6.894 18.805 ;
     RECT  2.304 18.797 2.718 18.959 ;
     RECT  3.708 18.805 7.038 18.995 ;
     RECT  3.852 18.995 7.038 19.381 ;
     RECT  7.815 18.029 12.294 19.381 ;
     RECT  2.304 18.959 2.697 19.771 ;
     RECT  13.032 18.797 14.274 19.819 ;
     RECT  15.408 18.797 19.818 19.819 ;
     RECT  2.304 19.771 2.754 19.921 ;
     RECT  3.852 19.381 12.294 19.921 ;
     RECT  13.032 19.819 19.818 19.949 ;
     RECT  21.492 19.819 21.51 19.949 ;
     RECT  15.408 19.949 19.818 20.039 ;
     RECT  21.42 20.011 21.474 20.203 ;
     RECT  21.348 20.203 21.474 20.317 ;
     RECT  21.204 20.317 21.474 20.345 ;
     RECT  21.204 20.345 21.222 20.429 ;
     RECT  18.144 20.039 19.818 20.779 ;
     RECT  18.144 20.779 20.502 20.849 ;
     RECT  2.304 19.921 12.294 20.893 ;
     RECT  13.032 19.949 14.274 20.893 ;
     RECT  0.144 20.635 0.162 20.909 ;
     RECT  15.408 20.039 17.334 20.965 ;
     RECT  18.144 20.849 19.818 20.965 ;
     RECT  2.304 20.893 14.274 21.067 ;
     RECT  2.268 21.067 14.274 21.163 ;
     RECT  15.408 20.965 19.818 21.163 ;
     RECT  2.268 21.163 19.818 21.191 ;
     RECT  2.268 21.191 12.294 21.227 ;
     RECT  13.032 21.191 19.818 21.263 ;
     RECT  13.032 21.263 16.197 21.293 ;
     RECT  13.032 21.293 14.274 21.389 ;
     RECT  15.408 21.293 16.197 21.389 ;
     RECT  0.108 21.541 0.126 21.581 ;
     RECT  17.1 21.263 19.818 21.659 ;
     RECT  2.304 21.227 12.294 21.695 ;
     RECT  2.304 21.695 12.186 21.821 ;
     RECT  13.032 21.389 13.59 21.929 ;
     RECT  15.732 21.389 16.197 21.929 ;
     RECT  13.104 21.929 13.497 22.109 ;
     RECT  4.104 21.821 12.186 22.199 ;
     RECT  0.54 22.207 0.558 22.253 ;
     RECT  4.5 22.199 12.186 22.541 ;
     RECT  0.108 22.411 0.198 22.556 ;
     RECT  2.304 21.821 3.33 22.621 ;
     RECT  0.144 22.556 0.162 22.733 ;
     RECT  14.796 22.855 14.814 22.891 ;
     RECT  15.915 21.929 16.197 22.891 ;
     RECT  4.5 22.541 12.15 23.009 ;
     RECT  14.796 22.891 16.197 23.009 ;
     RECT  18.54 21.659 19.818 23.009 ;
     RECT  17.1 21.659 17.334 23.089 ;
     RECT  18.54 23.009 19.782 23.089 ;
     RECT  17.1 23.089 19.782 23.125 ;
     RECT  4.5 23.009 11.682 23.251 ;
     RECT  14.616 23.125 14.634 23.279 ;
     RECT  17.064 23.125 19.782 23.279 ;
     RECT  15.915 23.009 16.197 23.323 ;
     RECT  17.064 23.279 18.897 23.323 ;
     RECT  2.304 22.621 3.51 23.431 ;
     RECT  4.248 23.251 11.682 23.431 ;
     RECT  2.304 23.431 11.682 23.549 ;
     RECT  15.915 23.323 18.897 23.819 ;
     RECT  19.692 23.279 19.782 23.819 ;
     RECT  15.915 23.819 17.118 23.899 ;
     RECT  15.408 23.899 17.118 23.935 ;
     RECT  19.764 23.819 19.782 23.963 ;
     RECT  14.796 23.935 17.118 24.089 ;
     RECT  4.176 23.549 11.682 24.139 ;
     RECT  15.408 24.089 16.938 24.197 ;
     RECT  18.54 23.819 18.897 24.197 ;
     RECT  2.304 23.549 3.402 24.283 ;
     RECT  2.232 24.283 3.402 24.331 ;
     RECT  4.176 24.139 12.114 24.331 ;
     RECT  15.732 24.197 16.938 24.359 ;
     RECT  2.232 24.331 12.186 24.395 ;
     RECT  0.324 24.331 0.342 24.461 ;
     RECT  2.304 24.395 12.186 24.503 ;
     RECT  15.915 24.359 16.938 24.629 ;
     RECT  2.304 24.503 10.797 24.899 ;
     RECT  2.304 24.899 9.558 25.079 ;
     RECT  12.168 24.503 12.186 25.079 ;
     RECT  2.304 25.079 9.486 25.169 ;
     RECT  14.616 24.097 14.634 25.169 ;
     RECT  0.108 25.003 0.198 25.313 ;
     RECT  2.304 25.169 9.234 25.387 ;
     RECT  0.18 25.313 0.198 25.469 ;
     RECT  2.268 25.387 9.234 25.475 ;
     RECT  2.304 25.475 9.234 25.547 ;
     RECT  2.415 25.547 9.234 25.853 ;
     RECT  4.716 25.853 9.234 25.979 ;
     RECT  2.415 25.853 3.474 26.159 ;
     RECT  2.415 26.159 3.438 26.477 ;
     RECT  5.115 25.979 9.234 26.519 ;
     RECT  5.115 26.519 7.002 27.139 ;
     RECT  4.608 27.139 7.002 27.337 ;
     RECT  4.392 27.337 7.002 27.365 ;
     RECT  2.415 26.477 3.366 27.481 ;
     RECT  4.392 27.365 5.706 27.481 ;
     RECT  7.74 26.519 9.234 27.599 ;
     RECT  6.48 27.365 7.002 27.679 ;
     RECT  7.74 27.599 8.097 27.679 ;
     RECT  2.415 27.481 5.706 27.691 ;
     RECT  2.304 27.691 5.706 27.869 ;
     RECT  8.928 27.599 9.234 27.869 ;
     RECT  6.48 27.679 8.097 27.905 ;
     RECT  7.344 27.905 8.097 28.013 ;
     RECT  3.456 27.869 5.706 28.123 ;
     RECT  6.48 27.905 6.498 28.123 ;
     RECT  3.456 28.123 6.498 28.139 ;
     RECT  7.416 28.013 8.097 28.139 ;
     RECT  8.928 27.869 8.946 28.139 ;
     RECT  3.996 28.139 5.634 28.157 ;
     RECT  6.408 28.139 6.426 28.175 ;
     RECT  7.488 28.139 8.097 28.175 ;
     RECT  3.996 28.157 5.397 28.205 ;
     RECT  2.304 27.869 2.697 28.247 ;
     RECT  2.34 28.247 2.697 28.301 ;
     RECT  0.54 27.913 0.558 28.363 ;
     RECT  7.632 28.175 8.097 28.409 ;
     RECT  3.996 28.205 4.014 28.445 ;
     RECT  0.216 28.363 0.558 28.459 ;
     RECT  0.108 28.459 0.558 28.589 ;
     RECT  0.108 28.589 0.126 28.685 ;
     RECT  2.415 28.301 2.697 29.987 ;
     RECT  5.115 28.205 5.397 29.987 ;
     RECT  7.815 28.409 8.097 29.987 ;
     RECT  10.515 24.899 10.797 29.987 ;
     RECT  13.215 22.109 13.497 29.987 ;
     RECT  15.915 24.629 16.197 29.987 ;
     RECT  18.615 24.197 18.897 29.987 ;
     RECT  2.415 29.987 2.505 30.257 ;
     RECT  5.115 29.987 5.205 30.257 ;
     RECT  7.815 29.987 7.905 30.257 ;
     RECT  10.515 29.987 10.605 30.257 ;
     RECT  13.215 29.987 13.305 30.257 ;
     RECT  15.915 29.987 16.005 30.257 ;
     RECT  18.615 29.987 18.705 30.257 ;
    LAYER M4 ;
     RECT  0.06 27.696 0.097 28.584 ;
     RECT  0.06 13.296 0.137 25.512 ;
     RECT  0.137 13.392 0.181 25.512 ;
     RECT  0.097 27.696 0.227 28.68 ;
     RECT  0.181 13.392 0.323 25.656 ;
     RECT  0.227 27.696 0.569 28.584 ;
     RECT  0.323 13.392 2.408 25.512 ;
     RECT  0.569 27.696 2.408 28.44 ;
     RECT  2.408 2.148 2.512 30.252 ;
     RECT  2.512 2.418 2.704 29.982 ;
     RECT  2.704 13.392 3.491 26.472 ;
     RECT  2.704 27.6 4.025 28.44 ;
     RECT  3.491 13.392 4.061 25.896 ;
     RECT  4.061 13.584 5.108 25.896 ;
     RECT  4.025 27.6 5.108 28.2 ;
     RECT  5.108 2.148 5.212 30.252 ;
     RECT  5.212 2.418 5.404 29.982 ;
     RECT  5.404 13.584 5.645 25.32 ;
     RECT  5.645 13.584 5.717 23.592 ;
     RECT  5.717 14.064 5.897 23.4 ;
     RECT  5.645 24.96 6.685 25.32 ;
     RECT  5.897 14.064 6.721 22.056 ;
     RECT  5.404 7.392 6.757 7.416 ;
     RECT  6.757 7.344 6.829 7.416 ;
     RECT  6.541 8.448 6.829 8.472 ;
     RECT  6.721 13.968 6.865 22.056 ;
     RECT  5.897 23.376 6.865 23.4 ;
     RECT  6.865 13.968 7.052 23.4 ;
     RECT  7.052 13.44 7.261 23.4 ;
     RECT  6.685 24.48 7.261 25.32 ;
     RECT  5.404 28.128 7.436 28.152 ;
     RECT  7.261 13.44 7.477 25.32 ;
     RECT  6.829 7.2 7.808 8.472 ;
     RECT  5.404 10.32 7.808 10.728 ;
     RECT  7.477 13.44 7.808 25.8 ;
     RECT  7.436 27.84 7.808 28.152 ;
     RECT  7.808 2.148 7.912 30.252 ;
     RECT  7.912 2.418 8.104 29.982 ;
     RECT  8.104 18 8.201 25.8 ;
     RECT  8.201 18.48 8.525 25.8 ;
     RECT  8.525 25.68 8.633 25.8 ;
     RECT  8.525 18.48 8.921 24.504 ;
     RECT  8.921 18.48 8.963 22.248 ;
     RECT  8.921 23.424 8.963 24.504 ;
     RECT  8.963 18.72 8.985 22.248 ;
     RECT  8.963 23.424 9.101 24.408 ;
     RECT  8.985 18.72 9.317 21.912 ;
     RECT  8.104 15.456 9.349 16.344 ;
     RECT  8.104 10.032 9.385 11.976 ;
     RECT  8.104 7.2 9.421 8.28 ;
     RECT  9.421 7.2 9.493 8.76 ;
     RECT  9.317 19.824 9.539 21.912 ;
     RECT  9.385 10.032 9.601 12.84 ;
     RECT  9.493 7.2 10.105 9 ;
     RECT  9.601 10.032 10.105 13.608 ;
     RECT  10.105 7.2 10.213 13.608 ;
     RECT  9.349 15.456 10.249 17.112 ;
     RECT  10.249 15.456 10.357 17.496 ;
     RECT  9.317 18.72 10.357 18.792 ;
     RECT  10.213 7.152 10.508 13.608 ;
     RECT  10.357 14.976 10.508 18.792 ;
     RECT  9.539 19.824 10.508 21.432 ;
     RECT  9.101 23.952 10.508 24.408 ;
     RECT  10.508 2.148 10.612 30.252 ;
     RECT  10.612 2.418 10.804 29.982 ;
     RECT  10.804 7.056 10.865 13.608 ;
     RECT  10.804 16.08 10.931 17.112 ;
     RECT  10.931 16.08 11.153 16.536 ;
     RECT  11.153 16.32 11.369 16.536 ;
     RECT  10.804 23.952 11.441 24.408 ;
     RECT  11.441 24.144 11.837 24.408 ;
     RECT  11.837 24.144 12.125 24.168 ;
     RECT  11.369 16.32 13.021 16.344 ;
     RECT  10.865 7.152 13.208 13.608 ;
     RECT  13.021 16.32 13.208 17.112 ;
     RECT  10.804 18.72 13.208 18.792 ;
     RECT  10.804 19.92 13.208 21.432 ;
     RECT  13.208 2.148 13.312 30.252 ;
     RECT  13.312 2.418 13.504 29.982 ;
     RECT  13.504 19.92 13.619 21.432 ;
     RECT  13.504 16.32 13.637 17.112 ;
     RECT  13.637 16.32 14.821 16.968 ;
     RECT  13.619 19.92 14.821 21.288 ;
     RECT  13.504 7.056 14.861 13.608 ;
     RECT  14.821 19.824 14.861 21.288 ;
     RECT  14.861 7.152 15.908 13.608 ;
     RECT  14.821 16.32 15.908 17.112 ;
     RECT  13.504 18.72 15.908 18.792 ;
     RECT  14.861 19.824 15.908 21.192 ;
     RECT  15.908 2.148 16.012 30.252 ;
     RECT  16.012 2.418 16.204 29.982 ;
     RECT  16.204 19.824 16.913 21.192 ;
     RECT  16.204 18.48 18.205 18.792 ;
     RECT  16.913 19.824 18.205 20.616 ;
     RECT  16.204 15.792 18.241 17.208 ;
     RECT  18.205 18.48 18.421 20.616 ;
     RECT  16.204 7.152 18.608 13.608 ;
     RECT  18.241 15.216 18.608 17.208 ;
     RECT  18.421 18.432 18.608 20.616 ;
     RECT  18.608 2.148 18.712 30.252 ;
     RECT  18.712 2.418 18.904 29.982 ;
     RECT  18.904 7.056 20.473 20.712 ;
     RECT  20.473 7.056 21.445 20.808 ;
     RECT  21.445 6.96 21.481 20.808 ;
     RECT  21.481 6.864 21.564 20.808 ;
    LAYER M5 ;
     RECT  2.4 2.137 2.52 2.151 ;
     RECT  5.1 2.137 5.22 2.151 ;
     RECT  7.8 2.137 7.92 2.151 ;
     RECT  10.5 2.137 10.62 2.151 ;
     RECT  13.2 2.137 13.32 2.151 ;
     RECT  15.9 2.137 16.02 2.151 ;
     RECT  18.6 2.137 18.72 2.151 ;
     RECT  13.2 2.151 13.512 7.189 ;
     RECT  13.2 7.189 13.656 7.379 ;
     RECT  14.832 9.877 14.856 10.163 ;
     RECT  21.408 9.877 21.432 10.163 ;
     RECT  7.8 2.151 8.112 13.429 ;
     RECT  5.1 2.151 5.412 13.621 ;
     RECT  2.4 2.151 2.712 14.101 ;
     RECT  5.1 13.621 5.64 14.387 ;
     RECT  0.192 14.197 0.216 14.435 ;
     RECT  7.104 13.429 8.112 15.349 ;
     RECT  2.4 14.101 3.576 15.443 ;
     RECT  10.5 2.151 10.812 15.637 ;
     RECT  6.864 15.349 8.112 16.069 ;
     RECT  9.36 15.637 10.812 16.069 ;
     RECT  6.864 16.069 10.812 16.259 ;
     RECT  5.1 14.387 5.412 16.501 ;
     RECT  7.488 16.259 10.812 16.501 ;
     RECT  7.488 16.501 10.92 16.595 ;
     RECT  7.8 16.595 10.92 17.123 ;
     RECT  5.1 16.501 6.312 17.509 ;
     RECT  0.144 17.941 0.168 18.227 ;
     RECT  18.6 2.151 18.912 18.421 ;
     RECT  18.432 18.421 18.912 18.755 ;
     RECT  4.464 17.509 6.312 19.427 ;
     RECT  7.8 17.123 10.812 20.051 ;
     RECT  21.408 20.053 21.432 20.435 ;
     RECT  5.1 19.427 6.072 20.579 ;
     RECT  9.6 20.051 10.812 20.627 ;
     RECT  7.8 20.051 8.112 20.965 ;
     RECT  5.1 20.579 5.412 21.061 ;
     RECT  6.912 20.965 8.112 21.061 ;
     RECT  13.2 7.379 13.512 21.253 ;
     RECT  13.2 21.253 13.608 21.443 ;
     RECT  6.912 21.061 8.328 21.491 ;
     RECT  9.504 21.397 9.528 21.923 ;
     RECT  7.104 21.491 8.328 22.213 ;
     RECT  7.104 22.213 8.952 22.259 ;
     RECT  2.4 15.443 2.712 23.029 ;
     RECT  2.304 23.029 2.712 23.219 ;
     RECT  4.368 21.061 5.412 23.269 ;
     RECT  0.288 20.869 0.312 24.277 ;
     RECT  0.144 24.277 0.312 24.467 ;
     RECT  7.8 22.259 8.952 24.515 ;
     RECT  4.272 23.269 5.412 24.707 ;
     RECT  0.288 24.467 0.312 25.621 ;
     RECT  0.192 25.621 0.312 25.667 ;
     RECT  7.8 24.515 8.472 25.715 ;
     RECT  7.8 25.715 8.232 25.765 ;
     RECT  7.488 25.765 8.232 25.811 ;
     RECT  4.512 24.707 5.412 25.907 ;
     RECT  2.4 23.219 2.712 26.437 ;
     RECT  7.488 25.811 8.112 27.875 ;
     RECT  2.4 26.437 3.48 28.115 ;
     RECT  0.192 25.667 0.216 28.691 ;
     RECT  2.4 28.115 2.712 30.249 ;
     RECT  5.1 25.907 5.412 30.249 ;
     RECT  7.8 27.875 8.112 30.249 ;
     RECT  10.5 20.627 10.812 30.249 ;
     RECT  13.2 21.443 13.512 30.249 ;
     RECT  15.9 2.151 16.212 30.249 ;
     RECT  18.6 18.755 18.912 30.249 ;
     RECT  2.4 30.249 2.52 30.263 ;
     RECT  5.1 30.249 5.22 30.263 ;
     RECT  7.8 30.249 7.92 30.263 ;
     RECT  10.5 30.249 10.62 30.263 ;
     RECT  13.2 30.249 13.32 30.263 ;
     RECT  15.9 30.249 16.02 30.263 ;
     RECT  18.6 30.249 18.72 30.263 ;
  END
END hbfd_lh0_136_WE
END LIBRARY
